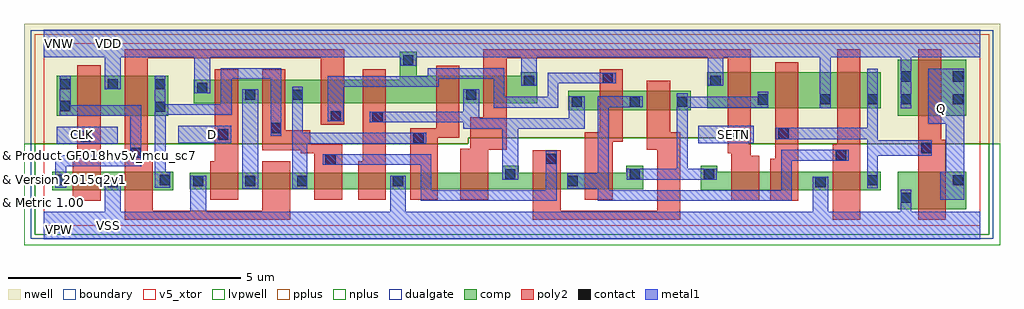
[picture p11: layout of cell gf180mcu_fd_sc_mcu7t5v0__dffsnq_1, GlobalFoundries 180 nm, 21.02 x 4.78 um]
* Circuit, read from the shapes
.subckt gf180mcu_fd_sc_mcu7t5v0__dffsnq_1 CLK D Q SETN VDD VNW VSS
XM1 VSS CLK n1 VSUBS nfet_05v0 w=0.405u l=0.6u
XM2 n2 n1 VSS VSUBS nfet_05v0 w=0.405u l=0.6u
XM3 n3 D VSS VSUBS nfet_05v0 w=0.36u l=0.6u
XM4 n4 n1 n3 VSUBS nfet_05v0 w=0.36u l=0.6u
XM5 n5 n2 n4 VSUBS nfet_05v0 w=0.36u l=0.6u
XM6 VSS n6 n5 VSUBS nfet_05v0 w=0.36u l=0.6u
XM7 n7 n4 VSS VSUBS nfet_05v0 w=0.36u l=0.6u
XM8 n6 SETN n7 VSUBS nfet_05v0 w=0.36u l=0.6u
XM9 n8 n2 n6 VSUBS nfet_05v0 w=0.36u l=0.6u
XM10 n9 n1 n8 VSUBS nfet_05v0 w=0.36u l=0.6u
XM11 n10 SETN n9 VSUBS nfet_05v0 w=0.405u l=0.6u
XM12 VSS n11 n10 VSUBS nfet_05v0 w=0.405u l=0.6u
XM13 n11 n8 VSS VSUBS nfet_05v0 w=0.405u l=0.6u
XM14 Q n11 VSS VSUBS nfet_05v0 w=0.815u l=0.6u
XM15 VDD CLK n1 VNW pfet_05v0 w=0.865u l=0.5u
XM16 n2 n1 VDD VNW pfet_05v0 w=0.865u l=0.5u
XM17 n3 D VDD VNW pfet_05v0 w=0.505u l=0.5u
XM18 n4 n2 n3 VNW pfet_05v0 w=0.505u l=0.5u
XM19 n12 n1 n4 VNW pfet_05v0 w=0.505u l=0.5u
XM20 VDD n6 n12 VNW pfet_05v0 w=0.505u l=0.5u
XM21 n6 n4 VDD VNW pfet_05v0 w=0.585u l=0.5u
XM22 VDD SETN n6 VNW pfet_05v0 w=0.585u l=0.5u
XM23 n8 n1 n6 VNW pfet_05v0 w=0.415u l=0.5u
XM24 n9 n2 n8 VNW pfet_05v0 w=0.415u l=0.5u
XM25 n9 SETN VDD VNW pfet_05v0 w=0.78u l=0.5u
XM26 VDD n11 n9 VNW pfet_05v0 w=0.78u l=0.5u
XM27 n11 n8 VDD VNW pfet_05v0 w=0.78u l=0.5u
XM28 Q n11 VDD VNW pfet_05v0 w=1.215u l=0.5u
.ends

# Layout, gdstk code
import gdstk
lib = gdstk.Library(unit=1e-6, precision=1e-09)
def R(c, l, rs):  # rectangles x0, y0, x1, y1
    for r in rs: c.add(gdstk.rectangle(r[:2], r[2:], *l))
def A(c, l, x, y, w, h, nx, ny, dx, dy):  # array of equal rectangles
    R(c, l, [(x+i*dx, y+j*dy, x+i*dx+w, y+j*dy+h) for i in range(nx) for j in range(ny)])
def P(c, l, *ps):  # polygons
    for p in ps: c.add(gdstk.Polygon(p, *l))
boundary = (0, 0)
nwell = (21, 0)
comp = (22, 0)
poly2 = (30, 0)
pplus = (31, 0)
nplus = (32, 0)
contact = (33, 0)
metal1 = (34, 0)
dualgate = (55, 0)
v5_xtor = (112, 1)
lvpwell = (204, 0)

gf180mcu_fd_sc_mcu7t5v0_ = lib.new_cell('gf180mcu_fd_sc_mcu7t5v0__dffsnq_1')
R(gf180mcu_fd_sc_mcu7t5v0_, boundary, [(0,0,20.16,3.92)])
P(gf180mcu_fd_sc_mcu7t5v0_, nwell, [(-0.43,1.76),(-0.43,4.35),(20.59,4.35),(20.59,1.76),(15.165,1.76),(15.165,1.885),(9.135,1.885),(9.135,1.76)])
R(gf180mcu_fd_sc_mcu7t5v0_, comp, [(18.385,0.345,19.865,1.16), (0.18,0.755,2.78,1.16), (0.28,2.36,2.68,3.225), (18.385,2.36,19.865,3.575), (11.295,2.485,13.925,2.9), (14.285,2.52,18.025,3.3)])
P(gf180mcu_fd_sc_mcu7t5v0_, comp, [(3.23,2.635),(3.23,3.14),(7.665,3.14),(7.665,3.74),(8.025,3.74),(8.025,3.22),(10.265,3.22),(10.265,3.3),(10.625,3.3),(10.625,2.635)],
  [(3.14,0.78),(3.14,1.14),(9.865,1.14),(9.865,1.285),(10.225,1.285),(10.225,1.14),(12.545,1.14),(12.545,1.285),(12.905,1.285),(12.905,0.78)],
  [(14.145,0.755),(14.145,1.285),(14.505,1.285),(14.505,1.16),(18.025,1.16),(18.025,0.755)])
P(gf180mcu_fd_sc_mcu7t5v0_, poly2, [(0.62,0.535),(0.62,1.38),(0.72,1.38),(0.72,3.45),(1.22,3.45),(1.22,0.535)],
  [(3.58,0.56),(3.58,1.38),(3.68,1.38),(3.68,3.36),(4.18,3.36),(4.18,0.56)],
  [(5.82,0.56),(5.82,1.555),(5.535,1.555),(5.535,1.62),(4.7,1.62),(4.7,3.36),(5.2,3.36),(5.2,2.05),(5.735,2.05),(5.735,1.755),(6.42,1.755),(6.42,0.56)],
  [(1.74,0.12),(1.74,3.8),(6.465,3.8),(6.465,2.175),(5.965,2.175),(5.965,3.6),(2.24,3.6),(2.24,1.38),(2.34,1.38),(2.34,0.32),(4.7,0.32),(4.7,1.38),(5.3,1.38),(5.3,0.12)],
  [(6.765,0.56),(6.765,1.38),(6.865,1.38),(6.865,3.36),(7.365,3.36),(7.365,0.56)],
  [(7.885,0.56),(7.885,2.095),(8.445,2.095),(8.445,3.44),(8.945,3.44),(8.945,1.895),(8.485,1.895),(8.485,0.56)],
  [(11.645,0.56),(11.645,2.005),(11.965,2.005),(11.965,3.36),(12.465,3.36),(12.465,1.805),(12.245,1.805),(12.245,0.56)],
  [(10.525,0.12),(10.525,1.62),(11.125,1.62),(11.125,0.32),(13.205,0.32),(13.205,1.635),(12.985,1.635),(12.985,3.12),(13.485,3.12),(13.485,2.005),(13.705,2.005),(13.705,0.12)],
  [(14.805,0.535),(14.805,1.555),(14.725,1.555),(14.725,3.6),(9.965,3.6),(9.965,1.635),(9.565,1.635),(9.565,0.56),(8.965,0.56),(8.965,1.655),(9.185,1.655),(9.185,2.335),(9.465,2.335),(9.465,3.8),(15.225,3.8),(15.225,1.505),(15.405,1.505),(15.405,0.535)],
  [(15.645,0.535),(15.645,1.44),(15.745,1.44),(15.745,3.52),(16.245,3.52),(16.245,0.535)],
  [(16.985,0.12),(16.985,1.755),(17.085,1.755),(17.085,3.8),(17.585,3.8),(17.585,0.12)],
  [(18.825,0.12),(18.825,3.8),(19.325,3.8),(19.325,1.85),(19.425,1.85),(19.425,0.12)])
P(gf180mcu_fd_sc_mcu7t5v0_, pplus, [(-0.2,1.76),(-0.2,4.12),(20.36,4.12),(20.36,1.76),(15.165,1.76),(15.165,1.885),(9.135,1.885),(9.135,1.76)])
P(gf180mcu_fd_sc_mcu7t5v0_, nplus, [(-0.2,-0.2),(-0.2,1.76),(9.135,1.76),(9.135,1.885),(15.165,1.885),(15.165,1.76),(20.36,1.76),(20.36,-0.2)])
A(gf180mcu_fd_sc_mcu7t5v0_, contact, 3.21, 0.85, 0.22, 0.22, 3, 1, 1.12, 0)
A(gf180mcu_fd_sc_mcu7t5v0_, contact, 0.35, 2.935, 0.22, 0.22, 3, 1, 1.02, 0)
R(gf180mcu_fd_sc_mcu7t5v0_, contact, [(18.455,0.485,18.675,0.705), (1.37,0.825,1.59,1.045), (16.615,0.825,16.835,1.045), (7.515,0.85,7.735,1.07), (11.275,0.85,11.495,1.07), (17.735,0.865,17.955,1.085), (19.575,0.865,19.795,1.085), (0.25,0.87,0.47,1.09), (2.49,0.87,2.71,1.09), (9.935,0.995,10.155,1.215), (12.615,0.995,12.835,1.215), (14.215,0.995,14.435,1.215), (6.06,1.31,6.28,1.53), (10.815,1.33,11.035,1.55), (17.055,1.405,17.275,1.625), (1.865,1.455,2.085,1.675), (18.895,1.56,19.115,1.78), (7.955,1.77,8.175,1.99), (0.79,1.805,1.01,2.025), (3.75,1.85,3.97,2.07), (14.795,1.85,15.015,2.07), (15.815,1.87,16.035,2.09), (4.89,1.99,5.11,2.21), (7.075,2.23,7.295,2.45), (6.175,2.245,6.395,2.465), (2.39,2.445,2.61,2.665), (0.35,2.465,0.57,2.685), (11.365,2.555,11.585,2.775), (12.615,2.555,12.835,2.775), (13.635,2.555,13.855,2.775), (15.375,2.605,15.595,2.825), (16.715,2.61,16.935,2.83), (17.735,2.61,17.955,2.83), (18.455,2.61,18.675,2.83), (19.575,2.61,19.795,2.83), (4.33,2.705,4.55,2.925), (5.35,2.705,5.57,2.925), (9.095,2.705,9.315,2.925), (3.3,2.85,3.52,3.07), (10.335,3.01,10.555,3.23), (14.355,3.01,14.575,3.23), (12.035,3.07,12.255,3.29), (18.455,3.1,18.675,3.32), (19.575,3.1,19.795,3.32), (7.735,3.45,7.955,3.67)])
R(gf180mcu_fd_sc_mcu7t5v0_, metal1, [(4.27,0.79,4.61,2.93), (0.28,1.765,1.59,2.13), (2.89,1.77,4.03,2.15), (14.09,1.77,15.285,2.15)])
P(gf180mcu_fd_sc_mcu7t5v0_, metal1, [(0.245,0.81),(0.245,1.51),(1.86,1.51),(1.86,2.36),(0.345,2.36),(0.345,3.225),(0.575,3.225),(0.575,2.595),(2.09,2.595),(2.09,1.28),(0.475,1.28),(0.475,0.81)],
  [(2.385,0.81),(2.385,3.225),(2.615,3.225),(2.615,2.615),(3.81,2.615),(3.81,3.39),(5.115,3.39),(5.115,1.93),(4.885,1.93),(4.885,3.16),(4.04,3.16),(4.04,2.38),(2.62,2.38),(2.62,1.15),(2.715,1.15),(2.715,0.81)],
  [(5.345,0.79),(5.345,2.985),(5.575,2.985),(5.575,1.995),(8.235,1.995),(8.235,1.765),(5.675,1.765),(5.675,0.79)],
  [(8.11,0.53),(8.11,1.305),(6,1.305),(6,1.535),(8.34,1.535),(8.34,0.76),(10.81,0.76),(10.81,1.615),(11.04,1.615),(11.04,0.53)],
  [(9.875,0.99),(9.875,2.08),(9.035,2.08),(9.035,2.225),(7.015,2.225),(7.015,2.455),(9.035,2.455),(9.035,2.93),(9.375,2.93),(9.375,2.31),(11.305,2.31),(11.305,2.78),(11.645,2.78),(11.645,2.08),(10.215,2.08),(10.215,0.99)],
  [(6.115,2.24),(6.115,3.215),(8.27,3.215),(8.27,3.39),(9.915,3.39),(9.915,2.775),(10.845,2.775),(10.845,3.295),(12.315,3.295),(12.315,3.065),(11.075,3.065),(11.075,2.54),(9.685,2.54),(9.685,3.16),(8.5,3.16),(8.5,2.985),(6.455,2.985),(6.455,2.24)],
  [(12.555,0.99),(12.555,1.22),(13.63,1.22),(13.63,2.845),(13.86,2.845),(13.86,2.775),(15.37,2.775),(15.37,2.885),(15.6,2.885),(15.6,2.54),(13.86,2.54),(13.86,1.22),(14.495,1.22),(14.495,0.99)],
  [(11.93,0.53),(11.93,0.79),(11.27,0.79),(11.27,1.13),(11.93,1.13),(11.93,2.78),(12.895,2.78),(12.895,2.55),(12.16,2.55),(12.16,0.76),(15.88,0.76),(15.88,1.63),(17.335,1.63),(17.335,1.395),(16.11,1.395),(16.11,0.53)],
  [(17.73,0.805),(17.73,1.86),(15.755,1.86),(15.755,2.105),(17.73,2.105),(17.73,3.38),(17.96,3.38),(17.96,1.84),(19.12,1.84),(19.12,1.5),(17.96,1.5),(17.96,0.805)],
  [(19.3,0.55),(19.3,1.16),(19.425,1.16),(19.425,2.19),(19.045,2.19),(19.045,3.38),(19.815,3.38),(19.815,0.55)],
  [(0,-0.3),(0,0.3),(1.31,0.3),(1.31,1.05),(1.65,1.05),(1.65,0.3),(3.15,0.3),(3.15,1.075),(3.49,1.075),(3.49,0.3),(7.455,0.3),(7.455,1.075),(7.795,1.075),(7.795,0.3),(16.555,0.3),(16.555,1.05),(16.895,1.05),(16.895,0.3),(18.45,0.3),(18.45,0.765),(18.68,0.765),(18.68,0.3),(20.16,0.3),(20.16,-0.3)],
  [(16.71,2.53),(16.71,3.62),(14.635,3.62),(14.635,3.005),(14.295,3.005),(14.295,3.62),(10.615,3.62),(10.615,3.005),(10.275,3.005),(10.275,3.62),(8.015,3.62),(8.015,3.445),(7.675,3.445),(7.675,3.62),(3.58,3.62),(3.58,2.845),(3.24,2.845),(3.24,3.62),(1.65,3.62),(1.65,2.93),(1.31,2.93),(1.31,3.62),(0,3.62),(0,4.22),(20.16,4.22),(20.16,3.62),(18.68,3.62),(18.68,2.53),(18.45,2.53),(18.45,3.62),(16.94,3.62),(16.94,2.53)])
R(gf180mcu_fd_sc_mcu7t5v0_, dualgate, [(-0.28,-0.28,20.44,4.2)])
R(gf180mcu_fd_sc_mcu7t5v0_, v5_xtor, [(0,0,20.16,3.92)])
P(gf180mcu_fd_sc_mcu7t5v0_, lvpwell, [(-0.43,-0.43),(-0.43,1.76),(9.135,1.76),(9.135,1.885),(15.165,1.885),(15.165,1.76),(20.59,1.76),(20.59,-0.43)])
gf180mcu_fd_sc_mcu7t5v0_.add(gdstk.Label('VSS', (1.4,0), layer=34, texttype=10))
gf180mcu_fd_sc_mcu7t5v0_.add(gdstk.Label('CLK', (0.84,1.96), layer=34, texttype=10))
gf180mcu_fd_sc_mcu7t5v0_.add(gdstk.Label('VDD', (1.4,3.92), layer=34, texttype=10))
gf180mcu_fd_sc_mcu7t5v0_.add(gdstk.Label('D', (3.64,1.96), layer=34, texttype=10))
gf180mcu_fd_sc_mcu7t5v0_.add(gdstk.Label('Q', (19.32,2.52), layer=34, texttype=10))
gf180mcu_fd_sc_mcu7t5v0_.add(gdstk.Label('SETN', (14.84,1.96), layer=34, texttype=10))
gf180mcu_fd_sc_mcu7t5v0_.add(gdstk.Label('& Vendor GLOBALFOUNDRIES', (0,2), layer=63, texttype=63))
gf180mcu_fd_sc_mcu7t5v0_.add(gdstk.Label('& Product GF018hv5v_mcu_sc7', (0,1.5), layer=63, texttype=63))
gf180mcu_fd_sc_mcu7t5v0_.add(gdstk.Label('& Version 2015q2v1', (0,1), layer=63, texttype=63))
gf180mcu_fd_sc_mcu7t5v0_.add(gdstk.Label('& Metric 1.00', (0,0.5), layer=63, texttype=63))
gf180mcu_fd_sc_mcu7t5v0_.add(gdstk.Label('VNW', (0.345,3.92), layer=21, texttype=10))
gf180mcu_fd_sc_mcu7t5v0_.add(gdstk.Label('VPW', (0.34,-0.085), layer=204, texttype=10))

lib.write_gds('gf180mcu_fd_sc_mcu7t5v0__dffsnq_1.gds')
